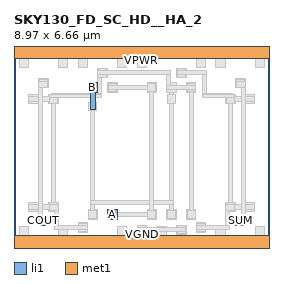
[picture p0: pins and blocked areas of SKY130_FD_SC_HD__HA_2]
MACRO SKY130_FD_SC_HD__HA_2
 CLASS CORE ;
 FOREIGN SKY130_FD_SC_HD__HA_2 0 0 ;
 SIZE 8.97 BY 6.66 ;
 ORIGIN 0 0 ;
 SYMMETRY X Y R90 ;
 SITE unit ;
  PIN VPWR
   DIRECTION INOUT ;
   USE POWER ;
   SHAPE ABUTMENT ;
    PORT
     CLASS CORE ;
       LAYER li1 ;
        RECT 0.00000000 6.42000000 8.97000000 6.90000000 ;
       LAYER met1 ;
        RECT 0.00000000 6.42000000 8.97000000 6.90000000 ;
    END
  END VPWR

  PIN VGND
   DIRECTION INOUT ;
   USE POWER ;
   SHAPE ABUTMENT ;
    PORT
     CLASS CORE ;
       LAYER li1 ;
        RECT 0.00000000 -0.24000000 8.97000000 0.24000000 ;
       LAYER met1 ;
        RECT 0.00000000 -0.24000000 8.97000000 0.24000000 ;
    END
  END VGND

  PIN COUT
   DIRECTION INOUT ;
   USE SIGNAL ;
   SHAPE ABUTMENT ;
    PORT
     CLASS CORE ;
       LAYER li1 ;
        RECT 0.87000000 0.58000000 1.20000000 0.91000000 ;
    END
  END COUT

  PIN SUM
   DIRECTION INOUT ;
   USE SIGNAL ;
   SHAPE ABUTMENT ;
    PORT
     CLASS CORE ;
       LAYER li1 ;
        RECT 7.77000000 0.58000000 8.10000000 0.91000000 ;
    END
  END SUM

  PIN A
   DIRECTION INOUT ;
   USE SIGNAL ;
   SHAPE ABUTMENT ;
    PORT
     CLASS CORE ;
       LAYER li1 ;
        RECT 3.28500000 0.80200000 3.61500000 1.13200000 ;
    END
  END A

  PIN B
   DIRECTION INOUT ;
   USE SIGNAL ;
   SHAPE ABUTMENT ;
    PORT
     CLASS CORE ;
       LAYER li1 ;
        RECT 2.67500000 4.66200000 2.84500000 5.25700000 ;
        RECT 2.59500000 5.25700000 2.92500000 5.58700000 ;
    END
  END B

 OBS
    LAYER polycont ;
     RECT 2.67500000 0.88200000 2.84500000 1.05200000 ;
     RECT 5.43500000 0.88200000 5.60500000 1.05200000 ;
     RECT 2.67500000 5.33700000 2.84500000 5.50700000 ;
     RECT 5.43500000 5.33700000 5.60500000 5.50700000 ;
     RECT 6.12500000 0.88200000 6.29500000 1.05200000 ;
     RECT 0.60500000 1.15200000 0.77500000 1.32200000 ;
     RECT 1.29500000 1.15200000 1.46500000 1.32200000 ;
     RECT 0.60500000 4.93200000 0.77500000 5.10200000 ;
     RECT 1.29500000 4.93200000 1.46500000 5.10200000 ;
     RECT 6.12500000 5.33700000 6.29500000 5.50700000 ;
     RECT 7.50500000 1.15200000 7.67500000 1.32200000 ;
     RECT 8.19500000 1.15200000 8.36500000 1.32200000 ;
     RECT 7.50500000 4.93200000 7.67500000 5.10200000 ;
     RECT 8.19500000 4.93200000 8.36500000 5.10200000 ;
     RECT 3.36500000 0.88200000 3.53500000 1.05200000 ;
     RECT 4.74500000 0.88200000 4.91500000 1.05200000 ;
     RECT 3.36500000 5.33700000 3.53500000 5.50700000 ;
     RECT 4.74500000 5.33700000 4.91500000 5.50700000 ;

    LAYER pdiffc ;
     RECT 0.95000000 5.48000000 1.12000000 5.65000000 ;
     RECT 3.02000000 5.84000000 3.19000000 6.01000000 ;
     RECT 5.78000000 5.84000000 5.95000000 6.01000000 ;
     RECT 0.26000000 6.19000000 0.43000000 6.36000000 ;
     RECT 1.64000000 6.19000000 1.81000000 6.36000000 ;
     RECT 2.33000000 6.19000000 2.50000000 6.36000000 ;
     RECT 3.71000000 6.19000000 3.88000000 6.36000000 ;
     RECT 4.40000000 6.19000000 4.57000000 6.36000000 ;
     RECT 6.47000000 6.19000000 6.64000000 6.36000000 ;
     RECT 7.16000000 6.19000000 7.33000000 6.36000000 ;
     RECT 8.54000000 6.19000000 8.71000000 6.36000000 ;
     RECT 7.85000000 5.48000000 8.02000000 5.65000000 ;

    LAYER ndiffc ;
     RECT 0.95000000 0.66000000 1.12000000 0.83000000 ;
     RECT 2.33000000 0.43000000 2.50000000 0.60000000 ;
     RECT 6.47000000 0.43000000 6.64000000 0.60000000 ;
     RECT 4.40000000 0.34200000 4.57000000 0.51200000 ;
     RECT 5.78000000 0.34200000 5.95000000 0.51200000 ;
     RECT 0.26000000 0.30000000 0.43000000 0.47000000 ;
     RECT 1.64000000 0.30000000 1.81000000 0.47000000 ;
     RECT 3.71000000 0.30000000 3.88000000 0.47000000 ;
     RECT 5.09000000 0.30000000 5.26000000 0.47000000 ;
     RECT 7.16000000 0.30000000 7.33000000 0.47000000 ;
     RECT 8.54000000 0.30000000 8.71000000 0.47000000 ;
     RECT 7.85000000 0.66000000 8.02000000 0.83000000 ;

    LAYER li1 ;
     RECT 2.59500000 0.80200000 2.92500000 1.13200000 ;
     RECT 5.35500000 0.80200000 5.68500000 1.13200000 ;
     RECT 2.67500000 4.66200000 2.84500000 5.25700000 ;
     RECT 2.59500000 5.25700000 2.92500000 5.58700000 ;
     RECT 5.43500000 4.93200000 5.60500000 5.25700000 ;
     RECT 5.35500000 5.25700000 5.68500000 5.58700000 ;
     RECT 0.87000000 0.58000000 1.20000000 0.91000000 ;
     RECT 0.87000000 5.40000000 1.20000000 5.73000000 ;
     RECT 2.25000000 0.35000000 2.58000000 0.68000000 ;
     RECT 6.04500000 0.80200000 6.37500000 1.13200000 ;
     RECT 0.52500000 1.07200000 0.85500000 1.15200000 ;
     RECT 1.21500000 1.07200000 1.54500000 1.15200000 ;
     RECT 0.52500000 1.15200000 1.54500000 1.32200000 ;
     RECT 0.52500000 1.32200000 0.85500000 1.40200000 ;
     RECT 1.21500000 1.32200000 1.54500000 1.40200000 ;
     RECT 0.52500000 4.85200000 0.85500000 4.93200000 ;
     RECT 1.21500000 4.85200000 1.54500000 4.93200000 ;
     RECT 0.52500000 4.93200000 1.54500000 5.10200000 ;
     RECT 0.52500000 5.10200000 0.85500000 5.18200000 ;
     RECT 1.21500000 5.10200000 1.54500000 5.18200000 ;
     RECT 6.04500000 5.25700000 6.37500000 5.58700000 ;
     RECT 2.94000000 5.76000000 3.27000000 6.09000000 ;
     RECT 6.39000000 0.35000000 6.72000000 0.68000000 ;
     RECT 7.42500000 1.07200000 7.75500000 1.15200000 ;
     RECT 8.11500000 1.07200000 8.44500000 1.15200000 ;
     RECT 7.42500000 1.15200000 8.44500000 1.32200000 ;
     RECT 7.42500000 1.32200000 7.75500000 1.40200000 ;
     RECT 8.11500000 1.32200000 8.44500000 1.40200000 ;
     RECT 7.42500000 4.85200000 7.75500000 4.93200000 ;
     RECT 8.11500000 4.85200000 8.44500000 4.93200000 ;
     RECT 7.42500000 4.93200000 8.44500000 5.10200000 ;
     RECT 7.42500000 5.10200000 7.75500000 5.18200000 ;
     RECT 8.11500000 5.10200000 8.44500000 5.18200000 ;
     RECT 5.70000000 5.76000000 6.03000000 6.09000000 ;
     RECT 0.18000000 6.11000000 0.51000000 6.42000000 ;
     RECT 1.56000000 6.11000000 1.89000000 6.42000000 ;
     RECT 2.25000000 6.11000000 2.58000000 6.42000000 ;
     RECT 3.63000000 6.11000000 3.96000000 6.42000000 ;
     RECT 4.32000000 6.11000000 4.65000000 6.42000000 ;
     RECT 6.39000000 6.11000000 6.72000000 6.42000000 ;
     RECT 7.08000000 6.11000000 7.41000000 6.42000000 ;
     RECT 8.46000000 6.11000000 8.79000000 6.42000000 ;
     RECT 0.00000000 6.42000000 8.97000000 6.90000000 ;
     RECT 4.32000000 0.26200000 4.65000000 0.59200000 ;
     RECT 5.70000000 0.26200000 6.03000000 0.59200000 ;
     RECT 0.00000000 -0.24000000 8.97000000 0.24000000 ;
     RECT 0.18000000 0.24000000 0.51000000 0.55000000 ;
     RECT 1.56000000 0.24000000 1.89000000 0.55000000 ;
     RECT 3.63000000 0.24000000 3.96000000 0.55000000 ;
     RECT 5.01000000 0.24000000 5.34000000 0.55000000 ;
     RECT 7.08000000 0.24000000 7.41000000 0.55000000 ;
     RECT 8.46000000 0.24000000 8.79000000 0.55000000 ;
     RECT 7.77000000 0.58000000 8.10000000 0.91000000 ;
     RECT 7.77000000 5.40000000 8.10000000 5.73000000 ;
     RECT 3.28500000 0.80200000 3.61500000 1.13200000 ;
     RECT 4.66500000 0.80200000 4.99500000 1.13200000 ;
     RECT 3.28500000 5.25700000 3.61500000 5.58700000 ;
     RECT 4.66500000 5.25700000 4.99500000 5.58700000 ;

    LAYER viali ;
     RECT 2.67500000 0.88200000 2.84500000 1.05200000 ;
     RECT 5.43500000 0.88200000 5.60500000 1.05200000 ;
     RECT 2.67500000 4.66200000 2.84500000 4.83200000 ;
     RECT 5.43500000 4.93200000 5.60500000 5.10200000 ;
     RECT 0.95000000 0.66000000 1.12000000 0.83000000 ;
     RECT 0.95000000 5.48000000 1.12000000 5.65000000 ;
     RECT 2.33000000 0.43000000 2.50000000 0.60000000 ;
     RECT 6.12500000 0.88200000 6.29500000 1.05200000 ;
     RECT 1.29500000 1.15200000 1.46500000 1.32200000 ;
     RECT 1.29500000 4.93200000 1.46500000 5.10200000 ;
     RECT 6.12500000 5.33700000 6.29500000 5.50700000 ;
     RECT 3.02000000 5.84000000 3.19000000 6.01000000 ;
     RECT 6.47000000 0.43000000 6.64000000 0.60000000 ;
     RECT 7.50500000 1.15200000 7.67500000 1.32200000 ;
     RECT 7.50500000 4.93200000 7.67500000 5.10200000 ;
     RECT 5.78000000 5.84000000 5.95000000 6.01000000 ;
     RECT 0.26000000 6.57500000 0.43000000 6.74500000 ;
     RECT 4.40000000 0.34200000 4.57000000 0.51200000 ;
     RECT 5.78000000 0.34200000 5.95000000 0.51200000 ;
     RECT 3.71000000 -0.08500000 3.88000000 0.08500000 ;
     RECT 7.85000000 0.66000000 8.02000000 0.83000000 ;
     RECT 7.85000000 5.48000000 8.02000000 5.65000000 ;
     RECT 3.36500000 0.88200000 3.53500000 1.05200000 ;
     RECT 4.74500000 0.88200000 4.91500000 1.05200000 ;
     RECT 3.36500000 5.33700000 3.53500000 5.50700000 ;
     RECT 4.74500000 5.33700000 4.91500000 5.50700000 ;

    LAYER met1 ;
     RECT 2.61500000 0.82200000 2.90500000 1.11200000 ;
     RECT 5.37500000 0.82200000 5.66500000 1.11200000 ;
     RECT 2.69000000 1.11200000 2.83000000 1.30200000 ;
     RECT 5.45000000 1.11200000 5.59000000 1.30200000 ;
     RECT 2.69000000 1.30200000 5.59000000 1.44200000 ;
     RECT 2.69000000 1.44200000 2.83000000 4.60200000 ;
     RECT 5.45000000 1.44200000 5.59000000 4.87200000 ;
     RECT 2.61500000 4.60200000 2.90500000 4.89200000 ;
     RECT 5.37500000 4.87200000 5.66500000 5.16200000 ;
     RECT 0.89000000 0.60000000 1.18000000 0.67500000 ;
     RECT 0.85000000 0.67500000 1.18000000 0.89000000 ;
     RECT 0.85000000 0.89000000 0.99000000 5.42000000 ;
     RECT 0.85000000 5.42000000 1.18000000 5.63500000 ;
     RECT 0.89000000 5.63500000 1.18000000 5.71000000 ;
     RECT 2.27000000 0.37000000 2.56000000 0.44500000 ;
     RECT 1.42500000 0.44500000 2.56000000 0.58500000 ;
     RECT 2.27000000 0.58500000 2.56000000 0.66000000 ;
     RECT 1.42500000 0.58500000 1.56500000 1.09200000 ;
     RECT 6.06500000 0.82200000 6.35500000 1.11200000 ;
     RECT 1.23500000 1.09200000 1.56500000 1.30700000 ;
     RECT 1.23500000 1.30700000 1.52500000 1.38200000 ;
     RECT 1.31000000 1.38200000 1.45000000 4.87200000 ;
     RECT 1.23500000 4.87200000 1.52500000 5.08200000 ;
     RECT 1.23500000 5.08200000 3.06000000 5.16200000 ;
     RECT 1.31000000 5.16200000 3.06000000 5.22200000 ;
     RECT 6.14000000 1.11200000 6.28000000 5.27700000 ;
     RECT 6.06500000 5.27700000 6.35500000 5.35200000 ;
     RECT 5.33500000 5.35200000 6.35500000 5.49200000 ;
     RECT 6.06500000 5.49200000 6.35500000 5.56700000 ;
     RECT 2.92000000 5.22200000 3.06000000 5.78000000 ;
     RECT 2.92000000 5.78000000 3.25000000 5.85500000 ;
     RECT 5.33500000 5.49200000 5.47500000 5.85500000 ;
     RECT 2.92000000 5.85500000 5.47500000 5.99500000 ;
     RECT 2.96000000 5.99500000 3.25000000 6.07000000 ;
     RECT 6.41000000 0.37000000 6.70000000 0.44500000 ;
     RECT 6.41000000 0.44500000 7.54500000 0.58500000 ;
     RECT 6.41000000 0.58500000 6.70000000 0.66000000 ;
     RECT 7.40500000 0.58500000 7.54500000 1.09200000 ;
     RECT 7.40500000 1.09200000 7.73500000 1.30700000 ;
     RECT 7.44500000 1.30700000 7.73500000 1.38200000 ;
     RECT 7.52000000 1.38200000 7.66000000 4.87200000 ;
     RECT 7.44500000 4.87200000 7.73500000 5.08200000 ;
     RECT 6.60000000 5.08200000 7.73500000 5.16200000 ;
     RECT 6.60000000 5.16200000 7.66000000 5.22200000 ;
     RECT 5.72000000 5.78000000 6.01000000 5.85500000 ;
     RECT 6.60000000 5.22200000 6.74000000 5.85500000 ;
     RECT 5.72000000 5.85500000 6.74000000 5.99500000 ;
     RECT 5.72000000 5.99500000 6.01000000 6.07000000 ;
     RECT 0.00000000 6.42000000 8.97000000 6.90000000 ;
     RECT 4.34000000 0.28200000 4.63000000 0.35700000 ;
     RECT 5.72000000 0.28200000 6.01000000 0.35700000 ;
     RECT 4.34000000 0.35700000 6.01000000 0.49700000 ;
     RECT 4.34000000 0.49700000 4.63000000 0.57200000 ;
     RECT 5.72000000 0.49700000 6.01000000 0.57200000 ;
     RECT 0.00000000 -0.24000000 8.97000000 0.24000000 ;
     RECT 7.79000000 0.60000000 8.08000000 0.67500000 ;
     RECT 7.79000000 0.67500000 8.12000000 0.89000000 ;
     RECT 7.98000000 0.89000000 8.12000000 5.42000000 ;
     RECT 7.79000000 5.42000000 8.12000000 5.63500000 ;
     RECT 7.79000000 5.63500000 8.08000000 5.71000000 ;
     RECT 3.30500000 0.82200000 3.59500000 0.89700000 ;
     RECT 4.68500000 0.82200000 4.97500000 0.89700000 ;
     RECT 3.30500000 0.89700000 4.97500000 1.03700000 ;
     RECT 3.30500000 1.03700000 3.59500000 1.11200000 ;
     RECT 4.68500000 1.03700000 4.97500000 1.11200000 ;
     RECT 3.30500000 5.27700000 3.59500000 5.35200000 ;
     RECT 4.68500000 5.27700000 4.97500000 5.35200000 ;
     RECT 3.30500000 5.35200000 4.97500000 5.49200000 ;
     RECT 3.30500000 5.49200000 3.59500000 5.56700000 ;
     RECT 4.68500000 5.49200000 4.97500000 5.56700000 ;

    LAYER via ;
     RECT 4.74500000 0.88200000 4.91500000 1.05200000 ;
     RECT 4.74500000 5.33700000 4.91500000 5.50700000 ;

    LAYER met2 ;
     RECT 4.68500000 0.82200000 4.97500000 1.11200000 ;
     RECT 4.76000000 1.11200000 4.90000000 5.27700000 ;
     RECT 4.68500000 5.27700000 4.97500000 5.56700000 ;

    LAYER via2 ;


    LAYER met3 ;


 END
END SKY130_FD_SC_HD__HA_2
